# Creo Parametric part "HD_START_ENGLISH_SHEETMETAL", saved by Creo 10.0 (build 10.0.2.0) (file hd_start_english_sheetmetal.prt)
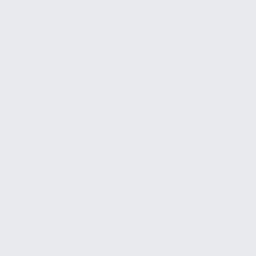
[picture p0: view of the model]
Units: Inch lbm Second (Pro/E Default); INCH, POUND, SECS
Materials in the file: DEFAULT

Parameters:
  PTC_MATERIAL_NAME = "DEFAULT"
  DRW_UNITS = "ENGLISH"
  TOL_NAME = "INCHES"
  SUR = "250"
  PTC_WM_ITERATION = "0"
  PTC_WM_VERSION = ".0"
  PTC_WM_CREATED_ON = "29-Feb-16 09:20:21 AM"
  PTC_WM_MODIFIED_ON = "29-Feb-16 09:20:21 AM"
  SMT_DFLT_BEND_REL_LENGTH_TYPE = "Through All"
  PTC_MASTER_MATERIAL = "DEFAULT"

Other parameters: SMT_THICKNESS, SMT_PART_BEND_ALLOWANCE_FACTOR, SMT_DFLT_BEND_RADIUS, SMT_DFLT_BEND_ANGLE, SMT_DFLT_CRNR_REL_WIDTH, SMT_DFLT_CRNR_REL_DEPTH, SMT_DFLT_BEND_REL_WIDTH, SMT_DFLT_BEND_REL_DEPTH, SMT_DFLT_BEND_REL_ANGLE, SMT_GAP, SMT_DFLT_EDGE_TREA_WIDTH, SMT_DFLT_MITER_CUT_WIDTH, SMT_DFLT_MITER_CUT_OFFSET, SMT_DFLT_BEND_REL_LENGTH

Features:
  1. datum plane "SIDE"
  2. datum plane "TOP"
  3. datum plane "FRONT"
  4. coordinate system
  5. datum point "PT_ORIG"

Other named items: CS_DEF, COMB0001, CONFIDENTIALITY, ANNOT_LAYER_STATE0001, ANNOT_LAYER_STATE0002

Layers: ANNOT, AXES, COSMETIC, CS, CURVES, CURVES2, DATUMS, DEF_CS, DEF_DATUMS, PTS, SURFS

Notes: THIS CAD DOCUMENT AND ALL INFORMATION DISCLOSED HEREIN ARE THE EXCLUSIVE  | PROPERTY OF  | THE HARLEY-DAVIDSON MOTOR COMPANY ("H-D"), AND ARE SUBMITTED TO THE RECIPIENT  | ONLY ON A  | CONFIDENTIAL BASIS. IN CONSIDERATION OF RECEIVING THIS CAD DOCUMENT, THE  | RECIPIENT AGREES:  | (1) NOT TO USE THIS CAD DOCUMENT OR ANY OF THE INFORMATION DISCLOSED HEREIN TO  | PRODUCE  | ANY PRODUCT OR FOR ANY OTHER PURPOSE EXCEPT AS AUTHORIZED IN WRITING BY H-D;  | (2) NOT TO  | REPRODUCE THIS CAD DOCUMENT; (3) TO RETURN THIS CAD DOCUMENT TO H-D UPON  | REQUEST; AND  | (4) THAT NO DISCLOSURE OF THIS CAD DOCUMENT OR ANY OF THE INFORMATION DISCLOSED  | HEREIN  | WILL BE MADE TO ANY THIRD PARTY WITHOUT THE PRIOR WRITTEN CONSENT OF H-D.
